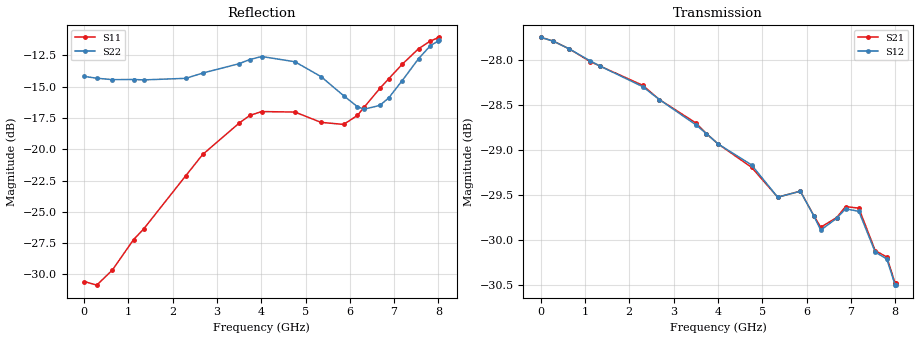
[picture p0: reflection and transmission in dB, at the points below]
! DEVICE ID: PE43712
! File Path: z:\PE43713\PE43713_CHAR_NOM_04292014\AMB\3p300\LS_ATT_26p50dB\PE43713_AMB_3p300V_3p000V_0p000V_LS_ATT_26p50dB_S2P_SN_10_A0139A.s2p
! Serial: 10
! Lot: A0139A
! Temp: 25C
! VDD: 3.300
! VSS: 0.000
! Control_Hi: 3.000
! Control_Lo: 0.000
! Attenuation Step: 26.50dB
! Port 1: RF1
! Port 2: RF2
! ThroughPath:1-2
! IDD: 0.0001451205
! ISS: -1.495e-007
#  Hz  S  RI  R  50
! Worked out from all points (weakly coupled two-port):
!   801 points, 10 MHz to 8.01 GHz, reference 50 ohm
!   highest |S21| = -27.74 dB at 10 MHz (marker M1); lowest = -30.5 dB at 8 GHz (marker M2)
!   lowest |S11| = -30.9 dB at 290 MHz (marker M3), VSWR 1.06, Z = 47.4 + j1.03 ohm
!   |S11| at or under -10 dB: start of sweep to end of sweep
!   |S22| runs from -16.9 to -11.3 dB; largest |S21 - S12| = 0.00016
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1e7  -0.0296 0.000774  0.041 -0.000164  0.041 -0.00015  -0.1955 0.00122
2.9e8  -0.0265 0.0109  0.0406 -0.00404  0.0406 -0.00404  -0.1912 0.0199
6.4e8  -0.0234 0.0231  0.0395 -0.00852  0.0395 -0.00852  -0.1851 0.0418
1.12e9  -0.0179 0.0397  0.0372 -0.014  0.0372 -0.0141  -0.1761 0.0713
1.35e9  -0.0133 0.0462  0.0359 -0.0165  0.0359 -0.0165  -0.1699 0.0835
2.3e9  0.0135 0.0773  0.0291 -0.0253  0.0291 -0.0252  -0.1337 0.1379
2.68e9  0.0267 0.0915  0.0257 -0.0278  0.0257 -0.0278  -0.1162 0.1647
3.5e9  0.0457 0.1186  0.0177 -0.0322  0.0177 -0.0321  -0.0894 0.2007
3.74e9  0.0496 0.1271  0.0152 -0.0329  0.0152 -0.0329  -0.0859 0.2114
4.01e9  0.0534 0.131  0.0125 -0.0335  0.0125 -0.0335  -0.0837 0.2193
4.76e9  0.0637 0.1256  0.0053 -0.0343  0.00535 -0.0344  -0.0656 0.2139
5.35e9  0.0803 0.0998  0.00031 -0.0334  0.000292 -0.0334  -0.0469 0.1894
5.86e9  0.1039 0.0707  -0.00419 -0.0334  -0.00417 -0.0334  -0.00775 0.1635
6.17e9  0.1241 0.0568  -0.00765 -0.0317  -0.00758 -0.0317  0.0244 0.146
6.32e9  0.1375 0.0522  -0.0081 -0.0311  -0.00803 -0.031  0.0436 0.1378
6.68e9  0.1698 0.0436  -0.0105 -0.0308  -0.0104 -0.0308  0.0886 0.1208
6.88e9  0.1873 0.0403  -0.0126 -0.0305  -0.0126 -0.0304  0.1108 0.1163
7.18e9  0.2148 0.0399  -0.0158 -0.0289  -0.0157 -0.0288  0.147 0.1171
7.55e9  0.2484 0.0434  -0.0181 -0.0254  -0.018 -0.0254  0.1935 0.1244
7.81e9  0.2658 0.0482  -0.0194 -0.0241  -0.0194 -0.024  0.2221 0.1324
8e9  0.2746 0.0516  -0.0197 -0.0225  -0.0196 -0.0225  0.2358 0.1349
8.01e9  0.275 0.0522  -0.0197 -0.0225  -0.0196 -0.0225  0.2365 0.1349
